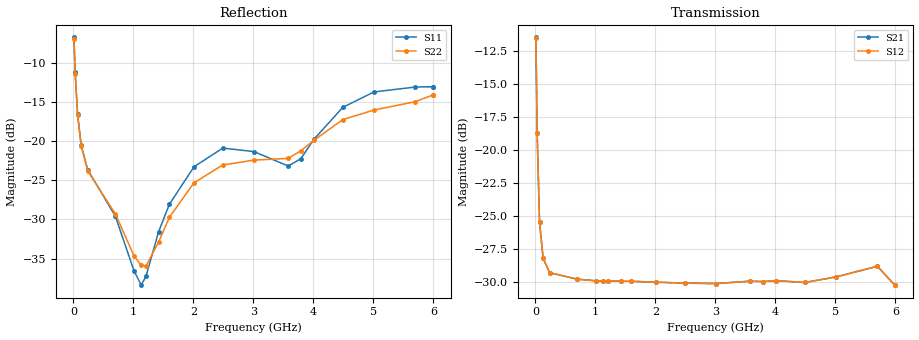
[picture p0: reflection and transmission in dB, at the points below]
! Integrated Device Technology
! Corporate Headquarters
! 6024 Silver Creek Valley Road
! San Jose, CA 95138  USA
! Phone:  1-408-284-8200
! Toll Free:  1-800-223-1366
! Webpage:  http://www.idt.com/
! Timing and RF Division
! 515 Groton Road, Suite 102
! Westford, MA 01886-6024
! Device:  F1951
! Description: 6-bit 0.5 dB Digital Step Attenuator
! Frequency:  100.0 -  4000.00 MHz
! Package:  4x4 mm Thin QFN Plastic Package: 24 pin
! Ports:  2 RF, 6 DC
!  Pin  1  = NC
!  Pin  2  = RF1  =  Port 1
!  Pin  3  = GND
!  Pin  4  = NC
!  Pin  5  = Serial Data Out (SDO)
!  Pin  6  = NC
!  Pin  7  = Reset Bar ( RSTb)
!  Pin  8  = Clock (CLK)
!  Pin  9  = Chip Select Bar (CSb)
!  Pin 10  = NC
!  Pin 11  = Serial Data In (SDI)
!  Pin 12  = NC
!  Pin 13  = NC
!  Pin 14  = VDD
!  Pin 15  = NC
!  Pin 16  = GND
!  Pin 17  = RF2  =  Port 2
!  Pin 18  = NC
!  Pin 19  = GND
!  Pin 20  = GND
!  Pin 21  = GND
!  Pin 22  = GND
!  Pin 23  = GND
!  Pin 24  = GND
! State:  58
! Atten State:  29.0 dB
! Voltage:  +3.30 Volts
! Current:  0.479 mA
! Data:  The device was measured on a F195X evaluation board which has
!  individual transmission lines to the RF pins.  Data was collected
!  de-embedded using a Automatic Fixture Removal [AFR] (Keysight Technologies).
!  The reference plane is the edge of the package pin.
! Misc:  Lot Code  1225BCA
!  Action Tracker AT0399
! Date Measured:  2018-09-13
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# GHz S dB R 50
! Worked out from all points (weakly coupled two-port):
!   600 points, 10 MHz to 6 GHz, reference 50 ohm
!   highest |S21| = -11.46 dB at 10 MHz (marker M1); lowest = -30.3 dB at 5.99 GHz (marker M2)
!   lowest |S11| = -38.4 dB at 1.13 GHz (marker M3), VSWR 1.02, Z = 48.8 + j0.238 ohm
!   |S11| at or under -10 dB: 24.02 MHz to end of sweep
!   |S22| runs from -36.3 to -6.9 dB; largest |S21 - S12| = 0.00013
!   S11 on the Smith chart (normalised r, x): 10 MHz: 1.75, -1.16; 30 MHz: 1.12, -0.59; 70 MHz: 0.97, -0.30; 1.21 GHz: 0.98, +0.02; 6 GHz: 0.81, +0.37
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0.01  -6.71 -34.4  -11.46 -41.8  -11.47 -41.8  -6.91 -34.6
0.03  -11.20 -62.8  -18.68 -63.1  -18.68 -63.2  -11.36 -62.4
0.07  -16.47 -87.4  -25.49 -52.4  -25.49 -52.4  -16.60 -87.3
0.13  -20.50 -106.3  -28.23 -35.2  -28.23 -35.2  -20.59 -105.9
0.24  -23.65 -123.0  -29.31 -22.3  -29.31 -22.2  -23.80 -122.9
0.7  -29.59 -136.6  -29.80 -14.4  -29.80 -14.4  -29.29 -138.8
1.01  -36.56 -158.5  -29.92 -15.5  -29.93 -15.5  -34.65 -154.3
1.13  -38.40 168.3  -29.94 -15.9  -29.94 -15.9  -35.87 -171.9
1.21  -37.28 144.1  -29.93 -16.3  -29.94 -16.3  -35.96 172.0
1.42  -31.59 117.8  -29.95 -17.9  -29.95 -17.9  -32.90 143.0
1.6  -28.06 114.9  -29.96 -19.3  -29.96 -19.3  -29.73 133.7
2.01  -23.27 122.8  -30.03 -23.0  -30.02 -23.0  -25.31 134.4
2.49  -20.87 135.5  -30.10 -27.1  -30.10 -27.1  -23.03 141.5
3.01  -21.32 145.4  -30.13 -31.3  -30.14 -31.3  -22.41 144.8
3.58  -23.16 124.1  -29.95 -36.0  -29.95 -36.0  -22.19 127.7
3.79  -22.24 108.4  -29.98 -37.8  -29.98 -37.7  -21.22 120.9
4.01  -19.74 100.1  -29.91 -39.7  -29.90 -39.7  -19.87 115.7
4.49  -15.66 98.6  -30.05 -43.2  -30.05 -43.2  -17.23 113.9
5.01  -13.69 107.4  -29.63 -44.6  -29.63 -44.6  -16.00 116.2
5.7  -13.06 112.3  -28.82 -56.5  -28.82 -56.5  -14.93 108.9
5.99  -13.02 106.4  -30.25 -57.9  -30.25 -57.9  -14.08 105.2
6  -13.02 106.1  -30.24 -57.2  -30.25 -57.2  -14.03 105.1
